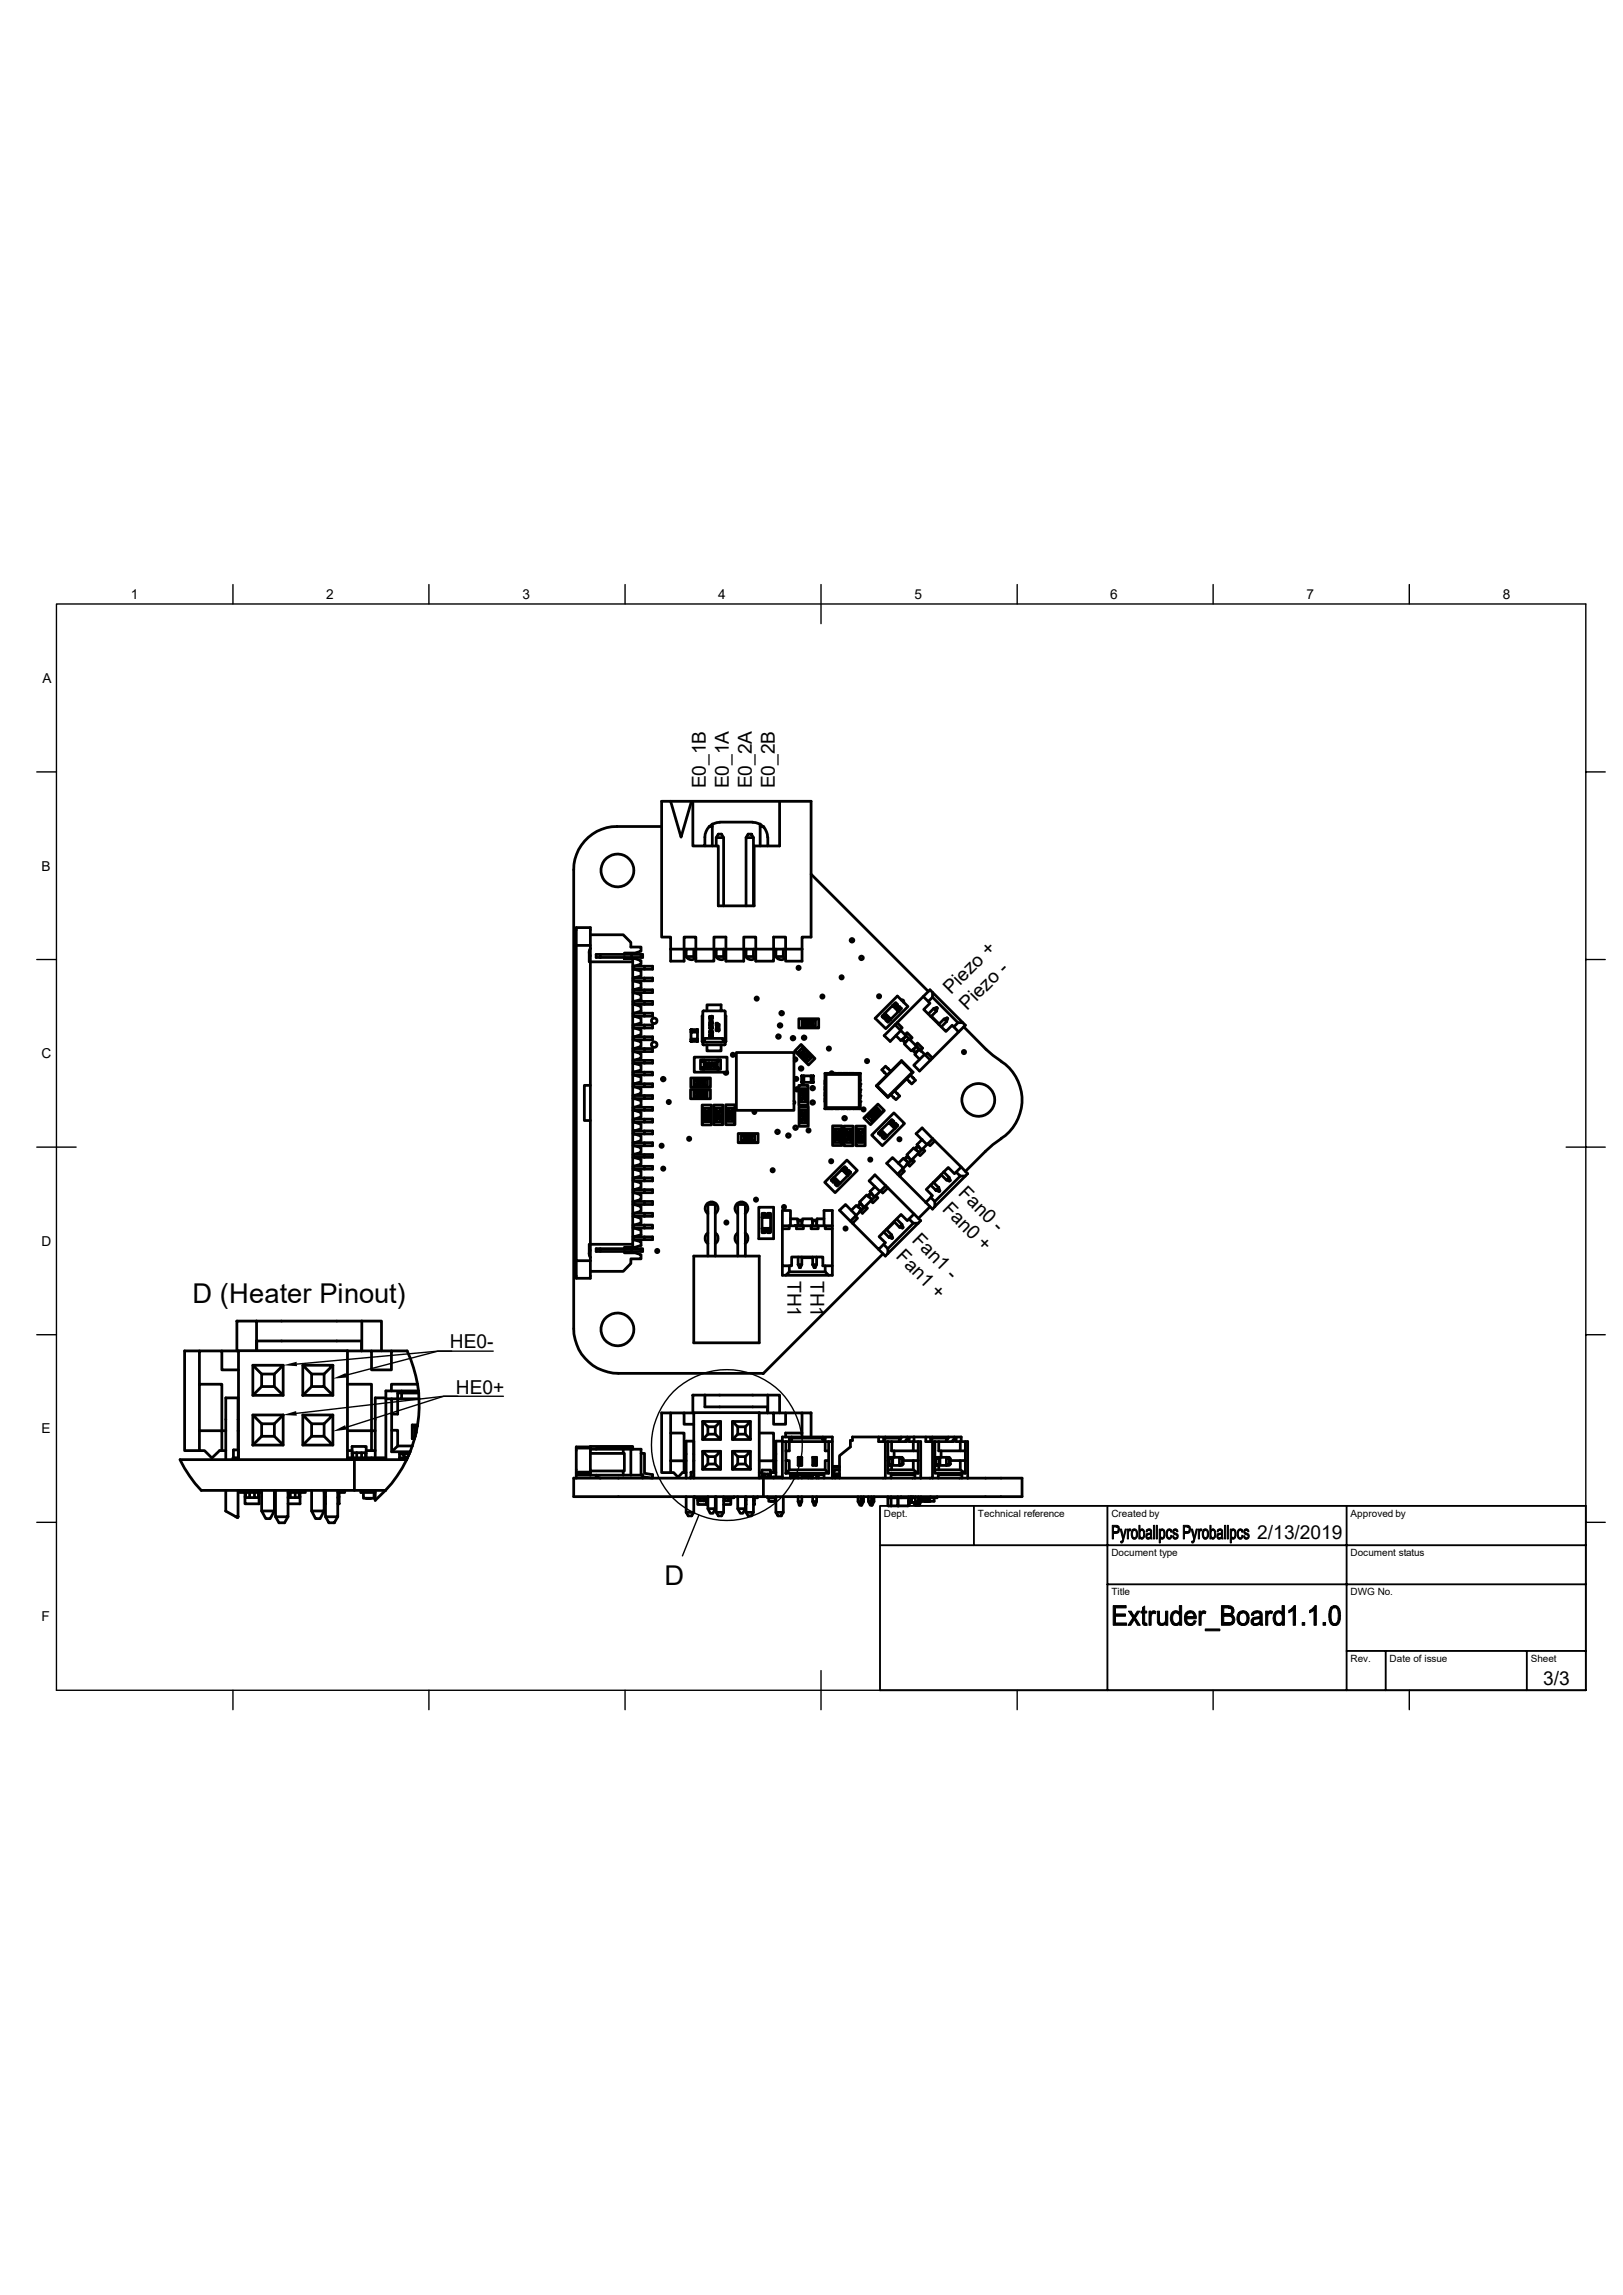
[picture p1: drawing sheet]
<svg xmlns="http://www.w3.org/2000/svg" width="297mm" height="420mm" viewBox="0 0 297 420" stroke-linecap="round" stroke-linejoin="round" font-family="sans-serif">
<defs><g id="words">
<g font-size="5">
<text x="35.2" y="238.4">D (Heater Pinout)</text>
<text x="121.6" y="290.1">D</text>
</g>
<g font-size="3.5">
<text x="129.2" y="144.3" transform="rotate(-90 129.2 144.3)">E0_1B</text>
<text x="133.4" y="144.3" transform="rotate(-90 133.4 144.3)">E0_1A</text>
<text x="137.6" y="144.3" transform="rotate(-90 137.6 144.3)">E0_2A</text>
<text x="141.8" y="144.3" transform="rotate(-90 141.8 144.3)">E0_2B</text>
<text x="174" y="182.1" transform="rotate(-45 174 182.1)">Piezo +</text>
<text x="177" y="185.1" transform="rotate(-45 177 185.1)">Piezo -</text>
<text x="172.3" y="221.4" transform="rotate(45 172.3 221.4)">Fan0 +</text>
<text x="175.2" y="218.4" transform="rotate(45 175.2 218.4)">Fan0 -</text>
<text x="166.8" y="227.1" transform="rotate(45 166.8 227.1)">Fan1 -</text>
<text x="163.8" y="230.1" transform="rotate(45 163.8 230.1)">Fan1 +</text>
<text x="144.1" y="234.4" transform="rotate(90 144.1 234.4)">TH1</text>
<text x="148.3" y="234.4" transform="rotate(90 148.3 234.4)">TH1</text>
<text x="82.3" y="246.8">HE0-</text>
<text x="83.4" y="255.1">HE0+</text>
<text x="230.1" y="281.7">2/13/2019</text>
<text x="282.4" y="308.4">3/3</text>
</g>
<g font-size="2.5">
<text x="24" y="109.6">1</text>
<text x="59.7" y="109.6">2</text>
<text x="95.6" y="109.6">3</text>
<text x="131.4" y="109.6">4</text>
<text x="167.3" y="109.6">5</text>
<text x="203.2" y="109.6">6</text>
<text x="239.1" y="109.6">7</text>
<text x="275" y="109.6">8</text>
<text x="7.7" y="125">A</text>
<text x="7.6" y="159.3">B</text>
<text x="7.6" y="193.7">C</text>
<text x="7.6" y="228">D</text>
<text x="7.6" y="262.3">E</text>
<text x="7.6" y="296.6">F</text>
</g>
<g font-size="1.8">
<text x="161.8" y="277.6">Dept.</text>
<text x="178.9" y="277.6">Technical reference</text>
<text x="203.4" y="277.6">Created by</text>
<text x="247.1" y="277.6">Approved by</text>
<text x="203.4" y="284.8">Document type</text>
<text x="247.1" y="284.8">Document status</text>
<text x="203.4" y="292">Title</text>
<text x="247.1" y="292">DWG No.</text>
<text x="247.1" y="304.2">Rev.</text>
<text x="254.3" y="304.2">Date of issue</text>
<text x="280.1" y="304.2">Sheet</text>
</g>
</g></defs>
<g fill="none" stroke="#000" stroke-width=".51">
<path d="M121.1 151.3h-8.2a7.9 7.9 0 0 0-7.9 7.9v84a8.2 8.2 0 0 0 8.2 8.1h26.5l21.9-21.9M122.7 146.6l1.9 6.6 1.9-6.6M126.8 146.6v8.2h2.2a3.9 3.9 0 0 1 .8-3.5 2.77 2.77 0 0 1 1.9-.8M129.8 151.3h.5M130.3 150.8v4M131.1 154.8v-1.5h1.3v12.5M131.1 153.3l.3-.6h.6l.4 .6M131.7 150.5h6.1M136.5 153.3l.4-.6h.6l.4 .6M137.8 150.5a2.75 2.75 0 0 1 2.7 2.7M139.1 150.8v4M139.1 151.3h.6l.1 .1"/>
<path d="M140.5 153.2v1.6M142.7 146.6v8.2h-4.7v11h-6.6v-11h-2.4M148.4 160l21.5 21.4M105.5 173v57.7h2.5M105.5 173v-3.2h2.5v64.1h-2.5v-3.2M105.5 173h2.5M107.8 174.3l.2 .6M108 173.6l-.2 .6v1.8h8M108 171.1h6l1.4 1.4v.8h1.9v.8l-1.1 .3h-1.9v.3M109.1 174.7h8.5v.5h-8.5zM109.9 174.7v.5M114.3 175.2v.2h1.5"/>
<path d="M115.6 174.7v.5M115.8 176v51.7h-8v1.8l.2 .6M115.8 175.4h.4l1.1 .4v.6l-1.4 .4v.6l1.4 .3v.9l-1.4 .3v.7l1.4 .3v.9l-1.4 .3v.6l1.4 .3v.9l-1.4 .3v.7l1.4 .3v.8l-1.4 .4v.6l1.4 .4v.8l-1.4 .3v.7l1.4 .3v.9l-1.4 .3v.6l1.4 .4v.8l-1.4 .4v.6l1.4 .3v.9l-1.4 .3v.6l1.4 .3v.9l-1.4 .3v.7l1.4 .3v.9l-1.4 .3v.6l1.4 .4v.8l-1.4 .3v.7l1.4 .3v.9l-1.4 .3v.6l1.4 .4v.8l-1.4 .4v.6l1.4 .3v.9l-1.4 .3v.7l1.4 .3v.8l-1.4 .4v.6l1.4 .3v.9l-1.4 .3v.7l1.4 .3v.9l-1.4 .3v.6l1.4 .3v.9l-1.4 .3v.7l1.4 .3v.8l-1.4 .4v.6l1.4 .4v.8l-1.4 .3v.7l1.4 .3v.9l-1.4 .3v.6l1.4 .4v.8l-1.4 .4v.6l1.4 .3v.9l-1.4 .3v.6l1.4 .3v.7l-1.1 .4h-.4M115.8 175.4v.6M115.9 176.8h3.5v.6h-3.5M115.9 179h3.5v.5h-1.5M117.3 174.7v.5M117.9 179v.5h-2M117.9 176.8v.6M122.7 173.7v-2.2h-1.6v-24.9h27.3v24.9h-1.6v2.2M122.7 173.7v2.2h2.5v-4.4h2.1v4.4h3.3v-4.4h2.2v4.4h3.3v-4.4h2.2v4.4h3.3v-4.4h2.2v4.4h3v-2.2M122.7 173.7h24.1"/>
<path d="M125.6 173.7v1.3h1.4v-1.3M125.6 173.8a1.14 1.14 0 0 0 .2 1.6 1.14 1.14 0 0 0 1.5-.1M131.1 173.8a1.14 1.14 0 0 0 .1 1.6 1.14 1.14 0 0 0 1.6-.1M131.1 173.7v1.3h1.3v-1.3M136.5 165.8v-12.5h1.4v12.5M136.5 173.8a1.14 1.14 0 0 0 .2 1.6 1.14 1.14 0 0 0 1.6-.1M136.5 173.7v1.3h1.4v-1.3M142 173.7v1.3h1.3v-1.3M142 173.8a1.14 1.14 0 0 0 .2 1.6 1.14 1.14 0 0 0 1.6-.1M108 198.6h-1.1v6.5h1.1M115.9 187.6h3.5v.5h-3.5M115.9 191.9h3.5v.5h-3.5"/>
<path d="M115.9 196.2h3.5v.5h-3.5M115.9 181.1h3.5v.6h-1.5M115.9 183.3h3.5v.5h-3.5M115.9 185.4h3.5v.6h-1.5M115.9 189.7h3.5v.6h-1.5M115.9 194.1h3.5v.5h-1.5M115.9 198.3h3.5v.6h-1.5M117.9 181.1v.6h-2M117.9 185.4v.6h-2M117.9 189.7v.6h-2M117.9 194.1v.5h-2M117.9 198.3v.6h-2"/>
<path d="M117.9 183.3v.5M117.9 187.6v.5M117.9 191.9v.5M117.9 196.2v.5M126.4 199.4h3.6v1.7h-3.6zM126.4 197.3h3.6v1.7h-3.6zM126.4 188.9h1.2v1.3h-1.2zM126.4 190.2v.4h1.2v-.4M126.4 188.9v-.5h1.2v.5M126.4 188.5h.1M126.4 188.8h.1M126.4 190.2h.1"/>
<path d="M126.4 190.5h.1M127 199.6h.3v.3h.2v.7h-.2v.2h-.3zM127 197.5h.3v.2h.2v.8h-.2v.2h-.3zM127 193.5h6.1v2.7h-6.1zM127.3 199.6h.2M127.3 197.5h.2M127.3 198.7h.2M127.5 199.6h1.4v1.2h-1.4zM127.5 197.5h1.4v1.2h-1.4zM127.6 197.9h.2l-.2 .3 .1 .1 .1-.1v.1l-.2-.1 .2-.3zM127.6 188.5h.1M127.6 188.8h.1"/>
<path d="M127.6 190.2h.1M127.6 190.5h.1M127.9 197.9l.3 .1-.1 .3-.2-.1zM128 197.9l.1 .1v.3l-.2-.1zM128.2 194h.4v.3h.3v1.1h-.3v.3h-.4zM128.3 197.9v.1h.2l-.2 .3zM128.3 198h.1l-.1 .2zM128.6 194h.3M128.6 195.7h.3M128.6 197.9a.2 .2 0 0 1 .3 .2 .2 .2 0 0 1-.3 .1zM128.6 185.1v6M128.6 185.9h-.1v4.7h.1"/>
<path d="M128.7 197.9l.1 .1-.1 .3-.1-.1zM128.7 191.1h4M128.7 185.1h4M128.9 194h2.3v1.7h-2.3zM128.9 199.6h.5v1.2h-.3M128.9 197.5h.6v1.2h-.4M128.9 194.6l.4-.1v.2a.18 .18 0 0 0-.2-.1 .18 .18 0 0 0 0 .3h.1l-.2 .2h.4l-.1 .1h-.4l.1-.3zM128.9 198.7h.2M128.9 190h3.4v.7h-3.4zM129.1 199.6v.3h-.2v.7h.2v.2M129.1 197.5v.2h-.2v.8h.2v.2M129.4 185v-1.1h2.6v1.1"/>
<path d="M129.4 191.2v1.1h2.6v-1.1M129.5 194.5a.37 .37 0 0 1 .5 .3 .37 .37 0 0 1-.4 .4l-.1-.3zM129.6 194.6l.2-.1 .1 .2-.1 .5-.3-.2zM129.8 186.6l.6-.2-.2 .1v.3l.2 .1zM129.8 187.6h.6h-.5v.1zM129.8 186.1l.5-.1 .1 .3h-.6zM129.8 188l.2-.1 .3 .2 .1-.2v.4l-.4-.4-.1 .1 .1 .2h-.1zM129.9 187.1h.2l-.1 .2h-.1zM129.9 187l.5 .2h-.2l-.1 .2h-.2zM129.9 189.4l.4-.1 .1 .4h-.6zM129.9 188.7l.3-.1 .1 .4-.1 .1h-.3zM129.9 186.1l.2 .1h-.2z"/>
<path d="M129.9 189.4l.3-.1 .1 .4h-.4zM130 186.6h.2v.2zM130.1 194.6h.4v.2l-.3 .4 .1-.3-.2-.1zM130.1 186.2h.2v-.2h-.1l-.1 .2M130.1 194.6l.2-.1 .2 .2-.3 .1zM130.2 188.3v.2zM130.7 194.6l.3-.1 .1 .2-.1 .5h-.3zM130.8 194.6h.3l-.1 .6a.35 .35 0 0 1-.3-.3 .35 .35 0 0 1 .1-.3zM131 187.2l.1 .3h.2v-.3v.3h.3h-.6zM131 187.7l.6-.1-.4 .1 .4 .2-.4 .2 .4 .2-.6-.1 .5-.3zM131.1 188.4l.1 .2 .3-.3 .1 .3-.1 .1 .1-.2-.2-.1-.3 .2zM131.2 194h.7v1.7h-.4"/>
<path d="M131.2 195.7h.3M131.5 194v.3h-.3v1.1h.3v.3M132.7 185.1v6M132.7 185.9h.1v4.7h-.1M133 196l.2 .3a.34 .34 0 0 1-.6 .3l-.1-.4M134.7 192.6h10.6v10.6h-10.6zM145.3 193.6l.2-.1 .3 .3-.1 .3-.4 .1M146.2 186.4h3.6v1.7h-3.6zM146.2 198.6h1.7v3.7h-1.7zM146.2 199.3l-.3-.3-.4 .2v.1v.2l.4 .2 .3-.3M146.4 199.7h1.2v1.4h-1.2zM146.4 199.2h1.2v.3h-.2v.2h-.7v-.2h-.3z"/>
<path d="M146.4 199.5v.2M146.6 191.1l2.5 2.6-1.1 1.2-2.6-2.5zM146.7 196.9h.1M146.7 198h.1M146.8 186.7h.3v.2h.2v.8h-.2v.2h-.3zM146.8 192.7l.3-.1-.2 .3zM146.8 192.6l.3-.1-.1 .4-.3-.1zM146.9 199.8l.3 .2 .1-.2v.3l-.3-.2h-.1v.2zM147 192.9l.4-.1-.3 .4zM147.1 192.9h.2l-.1 .1zM147.1 192l-.2 .1 .2 .2-.6 .5-.1-.1-.2 .1M147.1 192l-.3-.3-.8 .9 .4 .4"/>
<path d="M147.1 196.9h.1M147.1 198h.1M147.1 186.7h.2M147.1 192l.1 .1M147.1 187.9h.2M147.1 196.9h1.3v1.2h-1.3zM147.1 196.9h-.4v1.2h.4M147.2 192.1l1 1-.8 .8-1-.9zM147.3 186.7h1.4v1.2h-1.4zM147.4 187.1h.2l-.2 .1 .1-.1zM147.4 193h.2v.2l-.3 .2-.1-.2zM147.4 193.5l.4-.1-.1-.1h-.1h.2v.2h-.4l.2 .2z"/>
<path d="M147.4 187.3v-.1v.3l.2-.1v.1h-.2zM147.4 193.9l.1 .2M147.4 193l.1 .2-.2 .1-.1-.1zM147.6 199.5v.2M147.7 187.1h.3l-.1 .4h-.2zM147.7 187.1h.2v.4l-.2-.1zM148 187.1l.3 .1-.2 .3zM148 193.3l.2 .1 .1-.1 .3 .2-.9 .8-.2-.2 .2-.2-.2-.1zM148.1 187.2h.1l-.1 .2zM148.2 193.1l.1 .2M148.4 187.2h.2l-.1 .3-.1-.1zM148.4 187.1h.2a.25 .25 0 0 1 0 .2 .25 .25 0 0 1-.2 .2z"/>
<path d="M148.4 196.9h.4v1.2h-.4M148.4 196.9h.1M148.4 198h.1M148.7 186.7h.5v1.2h-.3M148.7 187.9h.2M148.8 196.9h.1M148.8 198h.1M148.9 186.7v.2h-.2v.8h.2v.2M151 196.4l.2 .2v6.1M151 199.9v.6M151 197.7v.7M151 198.8v.6"/>
<path d="M151.2 196.6h6M151.8 196.4l.3-.3h.2l.2 .3M152.2 196.4h.8M153.3 196.4h.7M154.4 196.4h.7M155.5 196.4h.7M157.4 196.4v6.5l-.2-.2v-6.1zM157.4 196.4h-6.4v6.5h1.2M157.4 196.4h.1M157.4 196.4v1.3M157.4 198.4v.4M157.4 199.4v.5"/>
<path d="M160.4 198.7l2.1 2.1zM161.7 186.4l-.3-.3 .4-.4 1 1-.4 .3-.3-.3M161.8 186.4h.3v.3M161.9 185.5l-.4 .5M161.9 185.4l1.1 1.2M163 186.6l-.5 .5-.1-.1M163 196l-.9-.9-.7 .7 .9 1M163 186.5v.1M163.3 184l1.1 1.1-1.4 1.4-1.1-1.1zM163.3 184l1.2 1.1h-.1M163.7 199.6l.9 1-.6 .7-1-1M163.8 187.5l6.5 6.5"/>
<path d="M163.9 183.6l-.5 .4M164 189.5l.8 .9 .9-.6M164.2 187.2l.9 .9-.4 .4M164.2 182.3l2 1.9-4.1 4.1-2-1.9zM164.6 184.2h-.3v-.3l-.3-.4-.4 .4 1 1 .3-.4-.3-.3M164.9 184.6l-.4 .5M164.9 183h.4l.1 .4M165 194.2v-.1l2.1 2.1h-.1M165 194.1l-4.6 4.6M165.2 190.2l.2 .5h.3M165.6 189.4l.4-.4 .9 .9-.4 .4M165.8 189.6l-.6 .6 .5 .5 .6-.6"/>
<path d="M166 190.4l-.5 .7 1.3 1.2 .7-.5M166.6 196.8l.9 .9-.7 .7-.9-1M167 196.2l-2-2-4.5 4.5M167 196.2l-4.5 4.5M167.1 196.2l-4.6 4.6M167.1 192.1v.3l.5 .2M167.5 191.3l.4-.4 .9 .9-.4 .4M167.7 191.5l-.6 .7 .5 .4 .6-.6M167.8 191.6l.5 .5M168.1 192.2l-.7 .8 .9 .8M168.3 192.1l.3 .2M169 182.4l1.2 1.2-1.2 1.1 4.1 4.1 1.1-1.2 1.2 1.2-4.8 4.8-.9-.9-.4 .4"/>
<path d="M169.2 193l-2 1.9 1.1 1.1 2.3-2.4M170.4 186l1.4 1.4M170.6 181.6v.9l-.7 .8M170.6 182.5l4.7 4.7M170.9 184.6l.5-.2 .1 .1-.1 .5zM170.9 184.6l-1 .9M171.4 185l-1.1 1.1M172.8 186.5l.5-.2 .1 .1-.2 .5zM172.8 186.5l-1 1M173.2 186.9l-.9 1M174.5 187.9l.8-.7h.9l.5 .4-1.3 1.2M176.2 187.2l-6-6.1-8.4 8.4 1.1 1.1 1.9-2"/>
<path d="M176.4 187.9a34 34 0 0 0 7.6 6.9 8.5 8.5 0 0 1-.8 13.6l-1.5 1.1-1.4 1.2-3.6 3.7M115.9 219.9h3.5v.5h-1.5M115.9 200.5h3.5v.5h-1.5M115.9 202.7h3.5v.5h-3.5M115.9 204.8h3.5v.6h-1.5M115.9 207h3.5v.5h-1.5M115.9 209.1h3.5v.6h-1.5M115.9 211.3h3.5v.5h-1.5M115.9 213.4h3.5v.6h-1.5M115.9 215.6h3.5v.5h-3.5M115.9 217.7h3.5v.6h-1.5M117.9 219.9v.5h-2"/>
<path d="M117.9 217.7v.6h-2M117.9 213.4v.6h-2M117.9 211.3v.5h-2M117.9 209.1v.6h-2M117.9 207v.5h-2M117.9 204.8v.6h-2M117.9 200.5v.5h-2M117.9 202.7v.5M117.9 215.6v.5M127.3 200.8h.2M127.6 200h.2l-.2 .2v.2l.2-.1v.1h-.2l.1-.3zM127.9 200.1h.2v.3h-.2z"/>
<path d="M127.9 200.1h.2v.3l-.2-.1zM128.2 200.1h.3l-.2 .3zM128.3 200.2h.1l-.1 .2zM128.5 202.2h1.7v3.7h-1.7zM128.6 200.1h.2l-.1 .3-.2-.1zM128.6 200.1h.2l-.1 .3-.1-.1zM128.7 203.3h1.2v1.5h-1.2zM128.7 205h.2v-.2h.8v.2h.2v.3h-1.2zM128.7 203.1h.2v.2h.8v-.2h.2M128.7 204.8v.2M128.9 200.8h.2M129.1 204.1h.4v.2l-.3 .1-.1-.1z"/>
<path d="M129.1 204.4l.2 .2h.2v-.2v.3l-.4-.2v.2zM129.1 203.5l.3-.1 .1 .2-.3 .1zM129.1 203.5h.3l.1 .1-.3 .1zM129.1 204.2l.4-.1v.2h-.3zM129.2 203.8l.3 .2h-.4h.1zM129.2 203.8l.2 .2h-.2zM129.4 204.4v.1M129.9 203.1v-.3h-1.2v.5M129.9 203.1v.2M129.9 204.8v.2M130.6 202.2h1.7v3.6h-1.7zM130.9 203.3h1.1v1.4h-1.1z"/>
<path d="M130.9 204.9h.2v-.2h.7v.2h.2v.4h-1.1zM130.9 203.1h.2v.2h.7v-.2h.2M130.9 204.7v.2M131.2 204.1l.3-.1 .2 .3h-.4zM131.2 204.4l.3 .2 .1-.2 .1 .2-.2 .1-.2-.2-.1 .2zM131.2 203.5l.4-.1 .1 .2-.4 .1zM131.3 204.1h.2l.1 .2h-.3zM131.3 203.8l.4 .2h-.5zM131.3 203.5h.3a.16 .16 0 0 1-.2 .2 .16 .16 0 0 1-.1-.2zM131.4 203.8l.2 .1h-.2zM131.5 204.4h.1M132 203.1v-.3h-1.1v.5"/>
<path d="M132 203.1v.2M132 204.7v.2M132.8 202.2h1.7v3.6h-1.7zM133.1 202.8h1.1v.3h-.2v.2h-.7v-.2h-.2zM133.1 204.9h.2v-.2h.7v.2h.2M133.1 203.1v.2M133.1 204.7v.2M133.4 204.1l.4-.1 .1 .1-.1 .2zM133.4 203.8l.4-.1 .1 .2-.4 .1zM133.4 204.4l.3-.1 .2 .2a.27 .27 0 0 1-.5 .1zM133.4 203.4h.2l.2 .2 .1-.2v.3l-.3-.3-.1 .1v.1zM133.5 203.8h.4l-.3 .2z"/>
<path d="M133.5 204.4h.2l.2 .1-.4 .1zM133.6 204.1h.1v.2zM134.2 203.3v1.4h-1.1M134.2 203.3h-1.1v1.4M134.2 204.7v.5h-1.1v-.3M134.2 203.1v.2M135.1 207.4h3.6v1.7h-3.6zM135.7 207.7h.3v.2h.2v.8h-.2v.2h-.3zM136 207.7h.2M136 208.9h.2M136.2 207.7h1.4v1.2h-1.4zM136.3 208h.3l-.3 .3 .1 .1 .1-.1-.1 .2-.1-.1 .1-.3z"/>
<path d="M136.6 208.1h.3l-.1 .4-.2-.1zM136.7 208.1l.2 .1-.1 .2-.2-.2zM136.9 208.2h.3l-.2 .3zM137 208.2h.2l-.2 .2zM137.3 208.1h.2v.4l-.3-.1zM137.4 208.1h.1l-.1 .3h-.1zM137.6 207.7h.5v1.2h-.3M137.6 208.9h.2M137.8 207.7v.2h-.2v.8h.2v.2M137.9 203.2l-.1 .1a.33 .33 0 0 0 .3 .5l.2-.3-.1-.3M145.3 201.5l.2 .1v.3l-.2 .1M146.2 202.5h1.7v3.6h-1.7z"/>
<path d="M146.4 201.4h.3v-.3h.7v.3h.2M146.4 201.1v.3M146.5 203.6h1.2v1.4h-1.2zM146.5 203.1h1.2v.3h-.3v.2h-.7v-.2h-.2zM146.5 205.2h.2v-.2h.7v.2h.3M146.5 203.4v.2M146.5 205v.2M146.9 204.4l.3-.1 .1 .1h-.1v.2zM146.9 204.1l.3-.1 .1 .2-.4 .1zM146.9 200.2l.3-.1 .1 .3h-.4zM146.9 200.8h.3l.1 .2-.4 .1zM146.9 203.8l.2-.1 .2 .2v-.2v.3l-.2-.3-.2 .1 .1 .1z"/>
<path d="M146.9 200.5h.4l-.1 .2zM146.9 204.8l.3-.1 .1 .2h-.4zM146.9 200.9l.3-.1v.2h-.3zM146.9 204.1l.3-.1 .1 .2-.3 .1zM146.9 204.7h.4v.2h-.4zM146.9 200.2h.3v.1l-.3 .1zM146.9 200.5h.3v.2zM147 204.4h.2v.2zM147.6 201.1v.6h-1.2v-.3M147.7 205v.5h-1.2v-.3M147.7 203.4v.2M150.9 216.4l4.1-4.1 1.9 1.9-4.1 4.1z"/>
<path d="M151 201v.6M152.4 206h1.7v3.6h-1.7zM152.4 216.4l-.3-.4 .4-.3 1 1-.4 .3-.3-.3M152.5 216.4h.3v.3M152.6 215.5l-.5 .4 .1 .1M152.6 207.1h1.2v1.4h-1.2zM152.6 206.6h1.2v.3h-.2v.2h-.8v-.2h-.2zM152.6 208.7h.2v-.2h.8v.2h.2M152.6 206.9v.2M152.6 208.5v.2M152.7 215.4l1.4-1.4 1.1 1.1-1.4 1.4zM152.7 215.4l-.1 .1 1.2 1"/>
<path d="M152.9 202.9h.4M153 207.6l.3-.1 .2 .1-.1 .2a.22 .22 0 0 1-.3 0 .22 .22 0 0 1-.1-.2zM153 207.3l.2-.1 .2 .2v-.2v.3l-.2-.3-.2 .1 .1 .2zM153 207.9h.4l-.1 .3zM153 208.2h.4l.1 .2-.3 .1-.2-.1zM153 207.6h.3l.1 .1-.3 .1zM153.1 208.2l.3 .1-.2 .1zM153.1 207.9h.2v.2zM153.7 216.6l-.5 .4M153.8 208.5v.6h-1.2v-.4M153.8 206.9v.2M154 202.9h.4"/>
<path d="M154.1 214l1.1 1.1M154.1 214h.1M154.4 206.1h1.7v3.6h-1.7zM154.6 213.6l-.5 .4M154.7 207.2h1.2v1.4h-1.2zM154.7 206.6h1.2v.4h-.2v.2h-.8v-.2h-.2zM154.7 208.8h.2v-.2h.8v.2h.2M154.7 207v.2M154.7 208.6v.2M154.9 213.8l-.3-.3-.3 .4 1 1 .4-.4-.4-.3h-.3v-.3M155 202.9h.5M155.1 207.9h.3l.1 .1h-.1v.2z"/>
<path d="M155.1 207.6h.3a.2 .2 0 0 1-.1 .3 .2 .2 0 0 1-.2-.3zM155.1 207.2l.3 .2 .1-.2v.3l-.2-.2h-.2v.2zM155.1 208.2h.4v.2l-.3 .1zM155.2 207.6h.2a.16 .16 0 0 1-.1 .2 .16 .16 0 0 1-.1-.2zM155.2 208h.2v.1zM155.2 208.2l.2 .1v.1h-.2zM155.6 214.5l-.4 .6M155.9 208.6v.5h-1.2v-.3M155.9 207v.2M156.1 202.9h1.3M156.6 206.1h1.7v3.6h-1.7zM156.9 207.2h1.2v1.4h-1.2z"/>
<path d="M156.9 208.8h.2v-.2h.8v.2h.2v.3h-1.2zM156.9 207h.2v.2h.8v-.2h.2M156.9 208.6v.2M157.2 208.2l.2 .2-.1-.1v.2zM157.2 208a.27 .27 0 0 1 .5 .1l-.3 .1zM157.2 202.7h-6l-.2 .2h6.4M157.3 207.3h.3v.1l-.3 .1zM157.3 208h.3l-.2 .2zM157.3 207.3l.2-.1 .2 .2-.4 .1zM157.3 207.6l.4 .2h-.5zM157.4 207.6l.2 .2h-.2zM157.4 200.5v.5"/>
<path d="M157.4 201.6v1.3M157.5 208.2l.1 .1v.2l-.2-.1h.2zM158.1 204.6l2.6-2.5 1.1 1.1-2.5 2.6zM158.1 207v-.4h-1.2v.6M158.1 207v.2M158.1 208.6v.2M158.9 204.2l.1 .1 .2-.1 .5 .5-.1 .2 .1 .1M158.9 204.2l-.2 .2 .8 .8 .4-.3M159 204l1.1-1 .8 .9-1 1zM159 204l-.1 .2M159.3 219.2l-.7-.5-1.3 1.3 .6 .7M159.4 204.2a.23 .23 0 0 1 .3 0 .23 .23 0 0 1 0 .3z"/>
<path d="M159.5 204.2h.2l.1 .2-.1 .1zM159.5 218.4l-.5 .3-.1 .2M159.5 207.7l4.1-4 1.9 1.9-4 4.1zM159.8 203.8l.3 .3h-.1l-.1 .2zM159.8 204l.2 .1-.1 .1zM159.9 203.7l.2-.1 .2 .2a.2 .2 0 0 1-.3 .2 .2 .2 0 0 1-.1-.3zM160 203.7l.3 .2a.21 .21 0 0 1-.3 0 .21 .21 0 0 1 0-.2zM160.1 219l-.7-.6-.5 .5 .7 .6M160.1 217.2l-.9 .9 .7 .8M160.1 203.5h.3v.3l.2-.1-.2 .1v-.3l-.2 .1zM160.2 202.9l.2-.2 .8 .8-.2 .2-.1-.2-.2 .2-.5-.5 .2-.2zM160.2 203.6h.1"/>
<path d="M160.2 202.9l-.1 .1M160.3 218.8l.4 .4-1 .9-.4-.3M161 218.1l-2-2 1.1-1.1 8.4 8.4-.5 .5h-.9l-.7-.8M161 203.7l-.1 .2M161.1 207.7l-.4-.3 .4-.3 1 1-.3 .3-.3-.3M161.1 207.8h.3v.3M161.2 206.9l-.4 .5M161.2 206.8l1.4-1.4 1.1 1.1-1.4 1.4zM161.2 206.8l1.1 1.2v-.1M162.1 217l-6.5 6.5M162.3 208l-.5 .4M162.5 217.4l-1 .9-.3-.4"/>
<path d="M162.7 205.4l1.1 1.1h-.1M162.7 205.4h-.1M163.2 205v-.1l-.5 .5M163.9 205.6h-.3v-.4l-.3-.3-.4 .4 1 .9 .4-.3-.3-.3M164.2 206h.1l-.5 .5M165.1 214l.4 .3-.9 .9 4.8 4.8M165.1 214l-.8 .9M165.3 213.8l-2-2-1 1.1 2.3 2.3M166.1 212.6l-.8-.6-.9 .9M166.2 212.9l-.3 .3M166.2 211.7h-.3l-.3 .5M166.7 212.4l-.6 .5"/>
<path d="M166.8 212.3l-.7-.6-.5 .5 .6 .6M167 212.1l.3 .4-.8 .9-.4-.4M167.9 210.7l-.7-.6-1.3 1.2 .6 .7M168.1 209.8l-.5 .2-.1 .3M168.7 210.4l-.7-.6-.5 .5 .7 .6M168.7 208.5l-.9 1 .7 .8M168.9 210.2l.3 .4-.8 .9-.4-.4M170.3 219.1l.8 .8v.9l-.5 .5-1.2-1.3M170.3 216.9l1 .9M170.7 208.4l6.4 6.4-6 6M170.7 208.4l-5.6 5.6M170.7 208.4l-2-2-1.1 1.1 2 2"/>
<path d="M170.8 216.4l1 .9M171.1 208.8l-.9 .9-.4-.4M171.8 217.3l.2 .6-.1 .2-.6-.3M171.8 217.3l-.5 .5M172.2 215l1 .9M172.3 215l-1.4 1.5M172.7 214.5l1 1M173.2 215.9l.5-.4 .2 .5-.2 .2zM175 214.5l.7 .7h1M175.7 215.2l-4.6 4.7M175.9 213.6l-1.2 1.2-1.2-1.1-4 4 1.1 1.1-1.2 1.2M108 228.8l-.2 .6"/>
<path d="M109.1 228.5h8.5v.5h-8.5zM109.9 228.5v.5M114.3 229v.3h1.9l1.1 .3v.8h-1.9v.8l-1.4 1.5h-6M115.6 228.5v.5M115.8 228.3h-1.5v.2M115.8 227.7v.6M115.9 224.2h3.5v.5h-3.5M115.9 222h3.5v.6h-3.5M115.9 226.4h3.5v.5h-1.5M117.3 228.5v.5M117.9 226.4v.5h-2M117.9 222v.6"/>
<path d="M117.9 224.2v.5M127 229.9h11.9v15.8h-11.9zM129.5 225.6a1.19 1.19 0 0 0 0 2M129.5 222.1a1.19 1.19 0 0 1-.2-1.7 1.19 1.19 0 0 1 1.8 0 1.19 1.19 0 0 1-.2 1.7M129.5 229.9v-9.5h1.4v9.5M130.9 225.6a1.19 1.19 0 0 1 0 2M135 222.1a1.19 1.19 0 0 1-.2-1.7 1.19 1.19 0 0 1 1.8 0 1.19 1.19 0 0 1-.2 1.7M135 225.6a1.19 1.19 0 0 0 0 2M135 229.9v-9.5h1.4v9.5M136.4 225.6a1.19 1.19 0 0 1 0 2M138.9 220.9h2.7v5.8h-2.7zM139.4 222.8h1.6v2h-1.6z"/>
<path d="M139.4 224.8l1.6 .1M139.4 222.8h1.6M139.4 224.9l.1 .6M139.5 222.1l-.1 .6M140.5 225.6l-.3-.3-.2 .3h-.5v-.5h1.4v.5h-.4M140.5 222l-.3 .3-.2-.3h-.5v.5h1.4v-.5h-.4M140.9 222.1l.1 .6M141 224.9l-.1 .6M141 224.8v.1M143.2 231.6v1.8h.6l.6-.7M143.2 224.9v6.7h1.7v-1.6h5.7v1.6h1.7M143.2 224.3h9.1"/>
<path d="M144.4 224.3v.6h-1.2M144.4 231.6v1.1M144.4 232.7h6.6M144.7 224.3v-2.8h-1.5v3.4M144.7 223.1h1.3v1M145.5 224.3h.4M145.8 224.3v.6h1.2v-.6M145.9 224.3h.7M146 223.4l.3-.1 .5 .1M146 231.4h.7l-.2 .6h-.2zM146 223.4h.7v.9M146 223.4v.9"/>
<path d="M146 230v1.4M146.7 223.9l.2-.8h1.7l.1 .8M146.7 230v1.4M146.7 230.2h2M148.4 224.3v.6h1.3v-.6M148.7 223.4l.5-.1 .2 .1M148.7 231.4h.7l-.2 .6h-.2zM148.7 230v1.4M149.4 223.4h-.7v.9M149.4 223.4v.9M149.4 230v1.4M150.8 223.1h-1.3l-.1 1"/>
<path d="M150.8 224.3v-2.8h1.5v11.9h-8.5M151 224.3v.6h1.3M151 232.7l.6 .7M151 231.6v1.1M156.7 222.4l-2-2-1.1 1.1 2.4 2.4M157.5 221.2l-.8-.6-.9 .9M157.6 221.5l-.3 .3M157.6 220.3h-.3l-.3 .6M158.1 221l-.6 .5M158.2 220.9l-.7-.6-.5 .5 .6 .6M158.4 220.7l.3 .4-.9 .9-.4-.3M161.7 227.8l.8 .7v.9l-.5 .5-1.2-1.3"/>
<path d="M161.7 225.5l1 .9M162.2 225l1 1M162.7 226.4l.5-.4 .2 .5-.2 .2zM163.6 223.6l1 1M163.7 223.6l-1.4 1.4M164.1 223.1l1 1M165.1 224.1l.2 .5-.2 .1-.5-.1zM167.1 223.9l-4.6 4.6M167.3 222.2l-1.3 1.2-1.1-1.1-4 4 1.1 1.1-1.2 1.2-4.8-4.7 .9-1-.4-.4M168 223.9l-5.5 5.5M170.2 220.9l-2.1 2.1M36.5 247.2h-2.7v18.3h2.7"/>
<path d="M40.6 247.2h3M43.6 250.7h-3v-3.5h-4.1v6.1M46.3 249.9h5.5l-1.6 1.6h-2.3zM46.3 249.9v5.5M46.3 259v5.5M46.9 241.8v5.4M47 247.2v-1.8h19.2v1.8M47.9 253.7l-1.6 1.7h5.5M47.9 251.5v2.2M50.2 251.5v2.2h-2.3M51.8 249.9v5.5l-1.6-1.7M51.8 259h-5.5l1.6 1.6h2.3"/>
<path d="M51.8 259v5.5l-1.6-1.7M51.8 259l-1.6 1.6M55.4 259h5.5l-1.6 1.6h-2.3zM55.4 249.9h5.5l-1.6 1.6h-2.3zM55.4 249.9v5.5M55.4 259v5.5M55.4 255.4h5.5M57 253.7l-1.6 1.7M57 251.5v2.2M59.3 251.5v2.2h-2.3M60.9 249.9v5.5l-1.6-1.7M60.9 259v5.5"/>
<path d="M63.6 247.2h4.4v3.5h3.6v-3.5h2.9a26.3 26.3 0 0 1 1.9 6.1M63.6 253.3h4.4v8.5h-4.4M66.2 241.8h3.6v5.4M66.2 241.8h-22.9v5.4M66.2 241.8v5.4M68 247.2h3.6M70.6 255.8h-1.9v11M73.5 254.6v.3h-.7v3.9h-1.1M73.5 256h3.2M76.4 253.3h-4.8v1.3M76.4 253.3l.2 1.3M76.6 254.6v.3"/>
<path d="M76.6 254.6h-6v1.4M76.6 254.9a23.5 23.5 0 0 1-.2 5.9M76.6 254.9h-3.1v1.1h-1.8M122.7 258.6h-1.6v10.9h1.6M125.2 258.6h1.8M129 255.3v2.2h11.5v1.1M138.9 258.6h2.7v2h2.2v-2h3v3.7M140.5 255.3h2.2v3.3M140.5 255.3v3.3M140.5 255.3h-13.7v3.3M141.6 258.6h2.2M146.8 258.6h1.6v4.4"/>
<path d="M32.9 267.1a22.8 22.8 0 0 0 3.9 5.7h28.1v-5.7h-31.9M36.5 261.8v-8.5h4.1v8.5h.7M36.5 261.8v3.7h.9l1.4 1.3 1.4-1.3h1.1M36.5 261.8h4.1v3.7M41.3 276.5l1.9 1.1M41.3 272.8v3.7M42.8 265.3v.1M43.2 277.6l.3 .1 .1-.1M43.2 277.6h.4M43.6 265.3v-9.5h-2.3v11.3M43.6 272.8v4.8M43.6 261.8h.1"/>
<path d="M43.6 266.8h-1v.3M43.6 267.1v-19.9h20v19.9M43.6 265.7v1.1M43.6 265.3h-.9v1.5M43.9 272.8v.3h4M44.8 273.9v1.3h2.6v-1.3M44.8 273.1v.8h.2M45 273.1v1h.7v-1M46.3 264.5h5.5M46.6 273.1v1M47.3 273.1v1h-1.6M47.4 273.1v.8h-.1"/>
<path d="M47.9 260.6v2.2M47.9 272.8v3.7M47.9 262.8l-1.6 1.7M50.2 260.6v2.2h-2.3M50.2 272.8v3.7h-2.3l.7 1.4h.8l.8-1.4M50.4 272.8v4.8h2.3v-4.8M50.4 277.6l.7 1.1h1l.6-1.1M53.1 273.1v1h-.4M54 273.1v1M54.7 273.1v1h-1.6M54.9 273.1v.8h-.2M54.9 273.9v1.3h-2.2"/>
<path d="M55.9 272.8v.3h-3.2M57 262.8l-1.6 1.7h5.5l-1.6-1.7M57 260.6v2.2M57 272.8v3.7M59.3 260.6v2.2h-2.3M59.3 272.8v3.7h-2.3l.7 1.4h.9l.7-1.4M59.3 273.1h.3M59.5 273.1l.1 .8M59.5 273.9l.1 1.3M59.6 272.8v4.8h2.2v-4.8M59.6 277.6l.6 1.1h1l.6-1.1M61.9 273.1v1h-.1"/>
<path d="M62.1 273.1v.8h-.2M62.1 273.9v1.3h-.3M63.1 272.8v.3h-1.3M63.6 266.8h4.4v.3M63.6 265.5h.8M64.4 265.9v-1.2h2.6v1.2M64.6 265.9h-.2v.9M64.9 267.1h9.5M64.9 272.8h5.7M65.3 265.9v.9M66 272.8v.3h2.7M66.2 266.8v-.9h.7v.9"/>
<path d="M66.2 265.9h-1.6v.9M66.5 273.1v1.1h2v-1.1M66.9 265.9h.1v.9M67 265.5h1.7M67.1 274.2h.7M68 266.8h2.6M68.7 261.8h-.7v3.7M71.7 261.7h1.1v2.9M73.1 266.8h1.1v.3M73.6 266.1l.8 .7 .3-.3 .2-.4M74.4 267.1v-.3h.2l-.2 .3M74.4 267.1a23.6 23.6 0 0 1-5.7 7.5v-1.8"/>
<path d="M74.9 266.1h-1.8v1M75.1 265.7h-3.4v-9.7h-1.1v11.1M75.1 265.7l-.2 .4M75.4 264.6h-2.6l-1.1 1.1M75.4 260.8v2.5M75.4 263.3h.5M75.4 264.6l-.3 1.1M75.9 261.2h.3v1M75.9 263.3l-.5 1.3M75.9 261.2v1.6M76 262.8l-.6 .5M76 262.8l-.1 .5"/>
<path d="M76.2 262.2l-.2 .6M76.4 260.8h-1l.5 .4M76.4 260.8l-.2 1.4M76.4 260.9l-.2 .3M105.5 265v4.4M105.5 269.6v.9M108 269.2h6v.8M108 264.8h-2.5v.2h2.5M108 269.4h-2.5v.2h2.5M108 265.2h9.3v4.8h-11.8M108 266h6M109.1 270v.2l.8 .3"/>
<path d="M109.1 265.2v-.1l.8-.3h5.7v.4M114 265.2v.8h.3v3.2h-.3M115.4 265.2v4.8M115.8 265.2v-.5h-7.8v5.3M117.3 269.9h.3v.6M117.3 266h.6v3.6l1.5 .3v.6l-1.8-.2M122.7 267.3v-5h2.5v5h.4M122.7 267.3v2.2h.6l.8 .8 .8-.8h.7M122.7 267.3h2.5v2.2M125.6 273.9v2.9h1.4M125.6 276.8l.3 .6h.7l.4-.6M126.4 269.5l.6-.1v-5.7h-1.4v6.8"/>
<path d="M126.4 269.5v.8M126.4 269.5h.1M127 269.6v.7h-.6v.2M127 270.5v-12h11.9v12M127 260.6h-1.8v-2h-2.5v3.7M127 273.9v2.9M127 267.3h.1M127.1 273.9v.2h2.4M127.7 274.6v.7h1.5v-.7M127.7 274.1l.1 .5M127.8 274.1v.6h.4v-.6M128.6 260.1h3.3l-1 1h-1.4z"/>
<path d="M128.6 265.6h3.3l-1 1h-1.4zM128.6 260.1v3.3M128.6 265.6v3.3M128.7 274.1v.6M129.2 274.1v.6h-1M129.2 274.1v.5M129.5 262.5l-.9 .9h3.3M129.5 267.9l-.9 1h3.3M129.5 261.1v1.4M129.5 266.6v1.3M129.5 273.9v2.2M130.9 261.1v1.4h-1.4"/>
<path d="M130.9 266.6v1.3h-1.4M130.9 273.9v2.2h-1.4l.5 .8h.5l.4-.8M131.1 273.9v2.9h1.3v-2.9M131.1 276.8l.3 .6h.6l.4-.6M131.9 260.1v3.3l-1-.9M131.9 265.6v3.3l-1-1M132.7 274.1v.6h-.3M133.2 274.1v.6M133.6 274.1v.6h-.9M133.7 274.6v.7h-1.3M133.7 274.1l-.1 .5M134 265.6h3.3l-.9 1h-1.4z"/>
<path d="M134 260.1h3.3l-.9 1h-1.4zM134 260.1v3.3M134 265.6v3.3M134.3 273.9v.2h-1.9M135 267.9l-1 1h3.3M135 262.5l-1 .9h3.3M135 261.1v1.4M135 266.6v1.3M135 273.9v2.2M136.4 266.6v1.3h-1.4M136.4 261.1v1.4h-1.4M136.4 273.9v2.2h-1.4l.5 .8h.4l.5-.8"/>
<path d="M136.4 274.1h.1M136.5 274.1v.5M136.5 274.6v.7M136.5 273.9v2.9h1.4v-2.9M136.5 276.8l.4 .6h.6l.4-.6M137.3 265.6v3.3l-.9-1M137.3 260.1v3.3l-.9-.9M138 274.1l-.1 .6M138 274.1v.5M138 274.6v.7h-.1M138.6 273.9v.2h-.7M138.9 270.3h2.7v.2"/>
<path d="M138.9 262.3h2.7v5h-2.7M138.9 269.5h.5M139.4 269.8v-.8h1.6v.8M139.5 269.8l-.1 .5M140 269.7v.6M140.4 273.9v.2h1.6M140.5 270.3v-.6h.4v.6M140.5 269.7h-1v.6M140.7 274.1v.6h1.2v-.6M140.9 269.8l.1 .5M141 274.7h.5M141 269.5h1"/>
<path d="M141.6 270.3h1.6M142 273.9v2.9h1.3v-2.9M142 267.3h-.4v2.2M142 276.8l.4 .6h.6l.3-.6M143.2 263.8h1.7v-.6h5.7v.6M143.2 270.5v-7.5h9.1v7.5M143.2 263.7h-1.2v6.6M143.8 263v-.7h3v.7M143.8 263.8v1.7M143.8 267.3v2.3M144.4 269h6.6M144.4 269l-.6 .6"/>
<path d="M144.7 270.5v-.6h6.1v.6M144.7 270.3h.6v.2M144.9 263v.2h-.5v2.3h-.6v1.8h.6v1.7M144.9 263.8h7.4M144.9 269.9l.5 .4 .5-.4M146 269.9v.6M146 266.7l.3 .3v.9l-.3 .3zM146 270.3h-.6v.2M146 274.8h.7l-.2 .7h-.2zM146 273.9v.9M146 266.7h.7M146.3 267.9l.4 .3h-.7"/>
<path d="M146.3 267h.2M146.5 267.9v-.9l.2-.3v1.5M146.7 270.3h1.2v.2M146.7 269.9v.6M146.7 273.9v.9M147.7 269.9v.4M147.9 270.3h.8M148.4 269.9v.6M148.7 274.8h.7l-.2 .7h-.2zM148.7 266.7v1.5l.3-.3v-.9M148.7 269.9v.6M148.7 273.9v.9"/>
<path d="M148.7 266.7h.7M148.7 266.7l.3 .3M149 267.9h.2l.2 .3h-.7M149 267h.2M149.2 267.9v-.9l.2-.3v1.5M149.4 270.3h.4v.2M149.4 269.9v.6M149.4 273.9v.9M150.6 263v.2h.4v2.3h.6M151 269l.6 .6M151.6 267.3v2.3h-7.8M151.6 267.3h-.6v1.7"/>
<path d="M151.6 263.8v3.5M152.3 270.3h.5v.2M152.3 268.6h1.3M152.3 268.4h1.3M152.3 269.7l1.2 .1M152.4 269.7v.6M152.8 269.7v.6h.8M153.1 269.7v.6M153.2 269.8v.5M153.6 269h-.9l-.1 .7M153.6 269.8h-.4v.5M157 274.8h.6v.7h-.2z"/>
<path d="M157 273.9v.9M157.6 273.9v.9h.4l-.3 .7h-.1M158 273.9v.9M158.9 274.8h.6v.7h-.2zM158.9 273.9v.9M159.5 273.9v.9h.4l-.3 .7h-.1M159.9 273.9v.9M160.8 263v.8h5.1l.5-.6v.6h2.1v6.7M161.7 263.6l.3-.4h2.9l-.4 .6M162 263v.2h-.3v.6M162 270.5h1.1v-.6h4.3v.6h-4.3M162 263.8v6.7h-57v3.4h34.7v-3.4"/>
<path d="M162.5 273.9v.2h2.4M162.5 266.7h2.6l.2 .3v.9M162.5 263.8v5.8h5.5v-2.3M162.5 274.1v1.4M162.5 269h4.6M162.5 275.5l.6 .1M162.7 266.7l.5 .3v.9l-.5 .3zM163.1 273.9v1.7M163.2 263.8v1.7h3.9v-1.7M163.2 266.7l.2 .3M163.2 267.9h.2l-.2 .3h-.7M163.2 267h.2"/>
<path d="M163.4 267v.9M163.6 265.5v1.2M164.3 273.9v1.7h-1.2M164.3 274.1l.1 1.5M164.6 266.7l.5 .3v.9l-.5 .3zM164.9 273.9v.2h1.4v-.2M164.9 263v.2M165.1 267.9h.2l-.2 .3h-1.9v.8M165.1 267h.2M165.3 267.3h1.8M166 263v.2h.4M166 263.2l-.4 .6"/>
<path d="M166.2 275.5l-1.9 .1M166.2 274.8h.5l-.5 .7M166.2 274.1v1.4M166.6 275h1v.5l.2-.1M166.7 274.1h.4M166.7 273.9v.9M166.8 273.9v1.1M166.8 274.1v.8M166.8 274.9h.1M167.1 273.9v.2h.4M167.1 269l.9 .6M167.1 265.5h.9"/>
<path d="M167.2 275l.2 .5h.2M167.3 263v.8M167.5 274.8h.6v.7h-.2zM167.5 273.9v.9M168 267.3h-.9v1.7M168 263.8v3.5M168.1 273.9v.9h.4l-.3 .7h-.1M168.5 273.9v.8v-.1h1.5v-.5v.5h-.2v.1h.3M168.5 274.1h1.8M168.6 274.7h.1M169 274.7h1.2M169.4 263v.8h5.1l.5-.6v.6h2.1v6.7"/>
<path d="M169.7 274.7v-.1h-1v.1h1.1M170.1 274.1v.6h.8v-.6M170.3 273.9v.2h1.2v-.2M170.3 263.6l.3-.4h2.9l-.4 .6M170.6 263v.2h-.3v.6M170.6 270.5h1.1v-.6h4.3v.6h-4.3M170.6 263.8v6.7h-3.2M171.1 266.7h2.6l.2 .3v.9M171.1 263.8v5.8h5.6v-2.3M171.1 269h4.6M171.3 266.7l.6 .3v.9l-.6 .3zM171.8 266.7l.2 .3v.9"/>
<path d="M171.8 263.8v1.7h3.9v-1.7M171.9 267.9h.1l-.2 .3v.8M171.9 267h.1M172.2 265.5v1.2M173.2 266.7l.5 .3v.9l-.5 .3zM173.5 263v.2M173.7 267h.2M173.7 267.9h.2M173.9 267.9l-.2 .3h-2.6M173.9 267.3h1.8M174.7 263v.2h.3M174.7 263.2l-.5 .6"/>
<path d="M175.7 265.5h1M175.7 269l1 .6M175.9 263.8v-.8h-19.9v.6h-.4v1.2l-2 1.6v4.1M176 270.5h11v3.4h-47.3M176.7 267.3h-1v1.7M176.7 263.8v3.5"/>
<circle cx="113" cy="159.3" r="2.99"/>
<circle cx="146.1" cy="177.1" r=".3"/>
<circle cx="154" cy="178.9" r=".3"/>
<circle cx="155.9" cy="172.1" r=".34"/>
<circle cx="157.7" cy="175.3" r=".34"/>
<circle cx="119.7" cy="191.2" r=".51"/>
<circle cx="119.7" cy="186.8" r=".51"/>
<circle cx="121.4" cy="197.5" r=".34"/>
<circle cx="130.1" cy="188.9" r=".28"/>
<circle cx="134.1" cy="193" r=".3"/>
<circle cx="138.5" cy="182.7" r=".3"/>
<circle cx="142.5" cy="189.7" r=".34"/>
<circle cx="142.8" cy="187.7" r=".34"/>
<circle cx="143" cy="185.4" r=".34"/>
<circle cx="145.1" cy="190" r=".34"/>
<circle cx="145.7" cy="197.4" r=".3"/>
<circle cx="146.6" cy="195.5" r=".34"/>
<circle cx="147.2" cy="189.9" r=".34"/>
<circle cx="148.7" cy="199.1" r=".34"/>
<circle cx="150.5" cy="182.4" r=".3"/>
<circle cx="151.7" cy="191.9" r=".3"/>
<circle cx="158.7" cy="194.2" r=".3"/>
<circle cx="160.9" cy="182.3" r=".3"/>
<circle cx="176.4" cy="192.5" r=".3"/>
<circle cx="121.1" cy="209.7" r=".3"/>
<circle cx="121.4" cy="213.9" r=".3"/>
<circle cx="122.4" cy="201.7" r=".3"/>
<circle cx="126.1" cy="208.4" r=".3"/>
<circle cx="138.3" cy="219.5" r=".3"/>
<circle cx="141.4" cy="214.2" r=".3"/>
<circle cx="142.3" cy="207.1" r=".34"/>
<circle cx="144.3" cy="207.8" r=".34"/>
<circle cx="145.6" cy="206.4" r=".34"/>
<circle cx="147.9" cy="206.9" r=".3"/>
<circle cx="148.7" cy="201.8" r=".34"/>
<circle cx="152.1" cy="212.5" r=".3"/>
<circle cx="154.6" cy="204.6" r=".34"/>
<circle cx="158" cy="203" r=".3"/>
<circle cx="159.3" cy="212.2" r=".3"/>
<circle cx="164.6" cy="208.5" r=".3"/>
<circle cx="179" cy="201.3" r="2.99"/>
<circle cx="120.3" cy="228.9" r=".3"/>
<circle cx="132.9" cy="223.7" r=".3"/>
<circle cx="143.5" cy="220.9" r=".3"/>
<circle cx="154.7" cy="224.8" r=".3"/>
<circle cx="113" cy="243.3" r="2.99"/>
</g>
<g fill="#000">
<circle cx="157.4" cy="198.4" r=".25"/>
<circle cx="157.4" cy="199.4" r=".25"/>
<circle cx="152.2" cy="202.9" r=".25"/>
<circle cx="153.3" cy="202.9" r=".25"/>
<circle cx="154.4" cy="202.9" r=".25"/>
<circle cx="155.5" cy="202.9" r=".25"/>
<circle cx="157.4" cy="201.6" r=".25"/>
<circle cx="157.4" cy="200.5" r=".25"/>
</g>
<g fill="none" stroke="#000" stroke-width=".25">
<path d="M10.3 110.5h279.9v198.8h-279.9zM42.6 107v3.5M78.5 107v3.5M114.4 107v3.5M150.2 107v7.1M186.1 107v3.5M222 107v3.5M257.9 107v3.5M6.7 141.3h3.6M290.2 141.3h3.6M6.7 175.6h3.6M290.2 175.6h3.6"/>
<path d="M6.7 209.9h7.2M286.6 209.9h7.2M6.7 244.3h3.6M82.6 247.3h-2.5l-25.8 2.3M83.7 255.5h-2.5l-27 3.2M90.3 247.3h-10.2l-16.8 4.4M92.1 255.5h-10.9l-17.9 5.7M290.2 244.3h3.6M6.7 278.6h3.6M127.9 277.3l-3 7.4M290.2 278.6h3.6M42.6 309.3v3.6"/>
<path d="M78.5 309.3v3.6M114.4 309.3v3.6M150.2 305.7v7.2M186.1 309.3v3.6M222 309.3v3.6M257.9 309.3v3.6"/>
<circle cx="133" cy="264.5" r="13.8"/>
</g>
<path d="M161 275.6h129.2v33.7h-129.2zM178.2 275.6v7.2M202.6 275.6v33.7M246.4 275.6v33.7M161 282.8h129.2M202.6 289.9h87.6M246.4 302.1h43.8M253.6 302.1v7.2M279.4 302.1v7.2" fill="none" stroke="#000" stroke-width=".34"/>
<g fill="#000" stroke="#000" stroke-width=".18">
<path d="M203.5 279.1h.9l.4 .3h-1v.9l.9 .1-.2 .2h-.7v1h-.3z" fill-rule="evenodd"/>
<path d="M204.2 279.4h.6l.1 .6-.2 .4-.9-.1h.5l.3-.1v-.5l-.2-.3z" fill-rule="evenodd"/>
<path d="M205 279.8h.2l.4 1.5-.2 .3z" fill-rule="evenodd"/>
<path d="M205.9 279.8h.2l-.5 2.2-.4 .1 .2-.2z" fill-rule="evenodd"/>
<path d="M206.3 279.8h.2v.3h.2l-.2 .4v1.1h-.2z" fill-rule="evenodd"/>
<path d="M206.6 279.9l.3-.1v.4l-.4-.1z" fill-rule="evenodd"/>
<path d="M207.3 279.9l.4-.1 .4 .4 .1 .9-.5 .6h-.3l-.2-.3h.5l.2-.2v-1l-.3-.2h-.4z" fill-rule="evenodd"/>
<path d="M208.4 279.1h.2v.9h.3l-.3 .4v.7l.2 .3h-.2v.2h-.2z" fill-rule="evenodd"/>
<path d="M208.6 280l.3-.2 .3 .1a1.57 1.57 0 0 1 .2 1.5l-.4 .3-.4-.2 .4-.1a.93 .93 0 0 0 0-1.4z" fill-rule="evenodd"/>
<path d="M209.9 279.9l.5-.1 .3 .2 .1 1.6h-.2v-.2h-.3l.2-.2v-.4l-.7-.1 .2-.1a.35 .35 0 0 0 .4-.1 .35 .35 0 0 0 0-.4l-.6-.1z" fill-rule="evenodd"/>
<path d="M212.3 280h.4z" fill-rule="evenodd"/>
<path d="M212.1 279.8h.2v.3h.3l-.3 .3v.7l.3 .3-.3 .1v.9h-.2z" fill-rule="evenodd"/>
<path d="M212.5 279.8a.57 .57 0 0 1 .7 .6v.7l-.2 .4-.4 .2-.3-.2a.78 .78 0 0 0 .7-.6 .78 .78 0 0 0-.2-.8l-.5-.1z" fill-rule="evenodd"/>
<path d="M213.7 279.8h.4l.3 .2h-.5l-.2 .2-.1 .8 .3 .4h-.3l-.2-.3v-.6z" fill-rule="evenodd"/>
<path d="M214.7 279.9l.6-.1 .3 .5h-.3l-.2-.3h-.4z" fill-rule="evenodd"/>
<path d="M216.5 279.1h.9l.4 .3h-1.1v.9l1 .1-.2 .2h-.8v1h-.2z" fill-rule="evenodd"/>
<path d="M217.2 279.4h.6v.6l-.1 .4-1-.1h.6l.3-.1v-.5l-.2-.3z" fill-rule="evenodd"/>
<path d="M218 279.8h.2l.4 1.5-.2 .3z" fill-rule="evenodd"/>
<path d="M218.9 279.8h.2l-.5 2.2-.4 .1 .2-.2z" fill-rule="evenodd"/>
<path d="M219.3 279.8h.2v.3h.2l-.2 .4v1.1h-.2z" fill-rule="evenodd"/>
<path d="M219.6 279.9l.3-.1v.4l-.4-.1z" fill-rule="evenodd"/>
<path d="M220.3 279.9l.4-.1 .4 .4v.9l-.4 .6h-.3l-.2-.3h.5l.2-.2v-1l-.3-.2h-.4z" fill-rule="evenodd"/>
<path d="M221.4 279.1h.2v.9h.3l-.3 .4v.7l.2 .3h-.2v.2h-.2z" fill-rule="evenodd"/>
<path d="M221.8 279.8l.4 .1a1.57 1.57 0 0 1 .2 1.5l-.4 .3-.4-.2 .4-.1a.93 .93 0 0 0 0-1.4h-.4z" fill-rule="evenodd"/>
<path d="M222.9 279.9l.5-.1 .3 .2 .1 1.6h-.2v-.2h-.3l.2-.2v-.4l-.7-.1 .2-.1a.41 .41 0 0 0 .5-.4l-.2-.2h-.5z" fill-rule="evenodd"/>
<path d="M225.3 280h.4z" fill-rule="evenodd"/>
<path d="M225.1 279.8h.2v.3h.3l-.3 .3v.7l.3 .3-.3 .1v.9h-.2z" fill-rule="evenodd"/>
<path d="M225.3 280l.2-.2a.57 .57 0 0 1 .7 .6v.7l-.2 .4-.4 .2-.3-.2a.78 .78 0 0 0 .7-.6 .78 .78 0 0 0-.2-.8z" fill-rule="evenodd"/>
<path d="M226.5 280l.4-.2 .5 .2h-.5l-.2 .3-.1 .7 .3 .4h-.3l-.2-.3z" fill-rule="evenodd"/>
<path d="M227.7 279.9l.6-.1 .3 .5h-.3l-.2-.3h-.4z" fill-rule="evenodd"/>
<path d="M205.1 282.1h.4l-.3 .3h-.1z" fill-rule="evenodd"/>
<path d="M203.7 293.8h2.4v.5h-2v1.1h1.9v.4h-1.9v1.2h2.1v.4h-2.5z" fill-rule="evenodd"/>
<path d="M206.5 294.9h.5l1.7 2.5h-.5z" fill-rule="evenodd"/>
<path d="M207.1 280.1l.5-.1-.1 .1a.99 .99 0 0 0-.2 1.1l.3 .2h-.4l-.1-.2-.1-.7z" fill-rule="evenodd"/>
<path d="M207.3 296.1l.3 .3-.7 1h-.5z" fill-rule="evenodd"/>
<path d="M208.1 294.9h.5l-.8 1.2-.3-.4z" fill-rule="evenodd"/>
<path d="M208.6 281.4h.4z" fill-rule="evenodd"/>
<path d="M209.1 294.2l.4-.3v1h.3v.3h-.3v1.7l.1 .2h-.5v-1.9h-.3v-.3h.3z" fill-rule="evenodd"/>
<path d="M209.8 280.1l.4-.1-.2 .2-.1 .2-.2-.1z" fill-rule="evenodd"/>
<path d="M209.1 297.1h.7l.1 .3a.56 .56 0 0 1-.8-.3z" fill-rule="evenodd"/>
<path d="M209.8 280.8h.7h-.1a.36 .36 0 0 0-.4 .2 .36 .36 0 0 0 .1 .4l.4 .1-.3 .2-.3-.1-.2-.3z" fill-rule="evenodd"/>
<path d="M210.1 281.4h.5z" fill-rule="evenodd"/>
<path d="M210.3 294.9h.3v.3h.4l-.2 .2-.1 .4v1.6h-.4z" fill-rule="evenodd"/>
<path d="M211.1 279.1h.2v2.5h-.2z" fill-rule="evenodd"/>
<path d="M210.9 294.9l.3-.1 .3 .1-.1 .4-.8-.1z" fill-rule="evenodd"/>
<path d="M211.6 279.1h.2v2.5h-.2z" fill-rule="evenodd"/>
<path d="M211.8 294.9h.4l.1 2 .2 .2h.8l-.4 .3h-.7l-.4-.5z" fill-rule="evenodd"/>
<path d="M212.7 297.1h.6z" fill-rule="evenodd"/>
<path d="M213.3 294.9h.4v2.5h-.4v-.3l-.3-.1 .3-.4z" fill-rule="evenodd"/>
<path d="M213.6 281.4h.4l.2-.4h.3l-.2 .5-.2 .2h-.3z" fill-rule="evenodd"/>
<path d="M214 280h.4l.1 .4h-.3z" fill-rule="evenodd"/>
<path d="M214.6 280.1l.5-.1-.2 .1a.41 .41 0 0 0 .4 .5l.3 .4-.1 .5-.3 .2h-.3l-.2-.3h.5a.37 .37 0 0 0 .1-.4 .37 .37 0 0 0-.4-.2l-.3-.3z" fill-rule="evenodd"/>
<path d="M214.6 281.1h.2l.2 .3h-.3z" fill-rule="evenodd"/>
<path d="M214.4 295.1l.7-.3h.3l.4 .3-.8 .1-.3 .3-.1 1.1 .2 .3 .3 .2h-.6l-.2-.3-.1-.8z" fill-rule="evenodd"/>
<path d="M214.5 297.1h1.4a.8 .8 0 0 1-1.2 .2z" fill-rule="evenodd"/>
<path d="M215.8 293.8h.4v3.6h-.3v-.3h-.5l.2-.1 .3-.5-.1-.8-.5-.6h.5z" fill-rule="evenodd"/>
<path d="M217 295.2l.8-.1a.67 .67 0 0 0-.6 .8h1.7v.3h-1.8l.2 .7 .5 .2h-.8l-.3-.6v-.7z" fill-rule="evenodd"/>
<path d="M217.1 295.1a1.03 1.03 0 0 1 1.6 .1l.2 .7h-1.7l1.3-.1-.3-.5-.2-.2h-1z" fill-rule="evenodd"/>
<path d="M218.1 282.1h.4l-.3 .3h-.1z" fill-rule="evenodd"/>
<path d="M217 297.1h1.1l.4-.5 .4 .1a1.06 1.06 0 0 1-1.4 .7z" fill-rule="evenodd"/>
<path d="M219.4 294.9h.4v.3h.4l-.3 .2-.1 .4v1.6h-.4z" fill-rule="evenodd"/>
<path d="M220.1 280.1l.5-.1-.1 .1a.99 .99 0 0 0-.2 1.1l.3 .2h-.4l-.2-.2v-.7z" fill-rule="evenodd"/>
<path d="M219.9 294.9l.4-.1 .4 .1-.1 .4-.8-.1z" fill-rule="evenodd"/>
<path d="M220.6 298.1h2.6v.4h-2.6z" fill-rule="evenodd"/>
<path d="M221.6 281.4h.4z" fill-rule="evenodd"/>
<path d="M222.8 280.1l.4-.1-.2 .2-.1 .2-.2-.1z" fill-rule="evenodd"/>
<path d="M222.8 280.8h.7h-.1a.36 .36 0 0 0-.5 .2 .36 .36 0 0 0 .2 .4l.4 .1-.3 .2-.3-.1-.2-.3z" fill-rule="evenodd"/>
<path d="M223.1 281.4h.5z" fill-rule="evenodd"/>
<path d="M224.1 279.1h.2v2.5h-.2z" fill-rule="evenodd"/>
<path d="M224.6 279.1h.2v2.5h-.2z" fill-rule="evenodd"/>
<path d="M223.5 293.8l1.6 .1 .6 .4h-1.8v1.1h1.6l-.2 .1 .5 .3h-1.9v1.2l1.9 .1-.2 .2-.6 .1h-1.5z" fill-rule="evenodd"/>
<path d="M224.7 294.3h1l.1 .3v.4l-.3 .4h-1.6h1a.55 .55 0 0 0 .5-.7 .55 .55 0 0 0-.7-.4z" fill-rule="evenodd"/>
<path d="M225 295.8h.8l.2 .7-.2 .6-1.9-.1h1.1l.5-.3v-.5l-.1-.2z" fill-rule="evenodd"/>
<path d="M226.6 295.2l.9-.1-.5 .3-.2 .5 .1 1 .6 .2h-.8l-.3-.3v-.9z" fill-rule="evenodd"/>
<path d="M226.6 281.4h.4l.2-.4h.3l-.1 .3-.3 .4h-.3z" fill-rule="evenodd"/>
<path d="M227 280h.4l.1 .4h-.3z" fill-rule="evenodd"/>
<path d="M226.7 295.1l.2-.2a1.21 1.21 0 0 1 1.4 .3l.2 .3a1.45 1.45 0 0 1-.8 2h-.5l-.5-.4h1.1l.3-.6a1.03 1.03 0 0 0-.5-1.4z" fill-rule="evenodd"/>
<path d="M227.6 280.1l.5-.1-.2 .1a.41 .41 0 0 0 .4 .5l.3 .4-.1 .5-.3 .2h-.3l-.2-.3h.5a.37 .37 0 0 0 .1-.4 .37 .37 0 0 0-.4-.2l-.3-.3z" fill-rule="evenodd"/>
<path d="M227.6 281.1h.2l.2 .3h-.3z" fill-rule="evenodd"/>
<path d="M229.1 295.2l.9-.1a.59 .59 0 0 0-.6 .6l-.4-.1z" fill-rule="evenodd"/>
<path d="M229.3 296.1h1.2l-.7 .2a.41 .41 0 0 0-.4 .5 .41 .41 0 0 0 .4 .3l.7 .1a.98 .98 0 0 1-1.6-.2l.1-.6z" fill-rule="evenodd"/>
<path d="M229.2 295.1a1.09 1.09 0 0 1 1.8 .3v1.6l.1 .4h-.4l-.1-.3h-.5l.4-.4v-.6h-1.2l1.1-.2a.39 .39 0 0 0 .1-.5 .39 .39 0 0 0-.3-.3z" fill-rule="evenodd"/>
<path d="M229.8 297.1h.8z" fill-rule="evenodd"/>
<path d="M231.6 294.9h.3v.3h.5l-.3 .2-.1 .4v1.6h-.4z" fill-rule="evenodd"/>
<path d="M232.2 294.9l.3-.1 .4 .1-.2 .4-.8-.1z" fill-rule="evenodd"/>
<path d="M233.2 295.1l.6-.3 .5 .1 .3 .2-.8 .1-.3 .3-.1 1.1 .2 .3 .3 .2h-.6l-.2-.3-.1-.8z" fill-rule="evenodd"/>
<path d="M233.3 297.1h1.4a.8 .8 0 0 1-1.2 .2z" fill-rule="evenodd"/>
<path d="M234.6 293.8h.4v3.6h-.3v-.3h-.5l.2-.1 .3-.5-.1-.8-.5-.6h.5z" fill-rule="evenodd"/>
<path d="M235.8 294.7l.3-.1h.5l-.7 .5z" fill-rule="evenodd"/>
<path d="M236.8 293.8h.3v3.6h-.5v-2.8h-.5z" fill-rule="evenodd"/>
<path d="M238.3 296.9h.5v.5h-.5z" fill-rule="evenodd"/>
<path d="M239.6 294.7l.3-.1h.6l-.8 .5z" fill-rule="evenodd"/>
<path d="M240.6 293.8h.3v3.6h-.4v-2.8h-.6z" fill-rule="evenodd"/>
<path d="M242.1 296.9h.5v.5h-.5z" fill-rule="evenodd"/>
<path d="M243.5 294.2h.7a.82 .82 0 0 0-.6 1v1.3l.3 .5 .3 .1-.7 .1-.3-.6v-1.3z" fill-rule="evenodd"/>
<path d="M243.5 294.2a.95 .95 0 0 1 1-.4 .95 .95 0 0 1 .7 .8l.1 1.1-.1 .8a1.14 1.14 0 0 1-.7 1h-.5l-.5-.3a1.16 1.16 0 0 0 1.2-.3l.2-.9-.1-1.4-.5-.4z" fill-rule="evenodd"/>
</g>
<path d="M51.8 259l2.4-.8 .1 .9zM51.8 249.9l2.5-.7 .1 .8zM60.9 252.3l2.3-1 .3 .8zM60.9 262l2.3-1.2 .2 .8z" fill="#000"/>
<use href="#words"/>
</svg>
